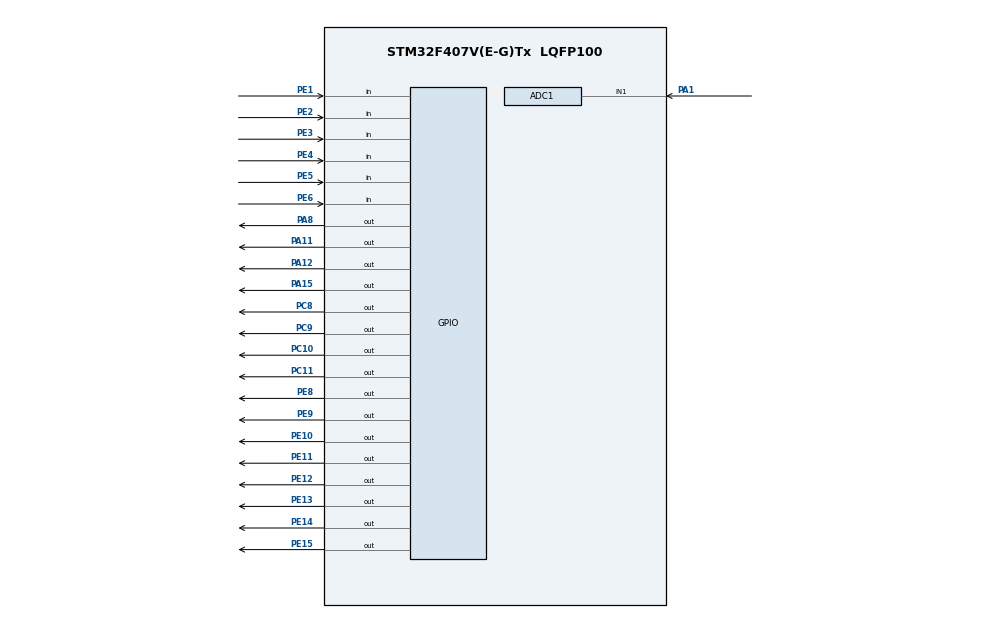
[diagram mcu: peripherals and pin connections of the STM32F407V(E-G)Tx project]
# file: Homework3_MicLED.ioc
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ADC1.Channel-3\#ChannelRegularConversion=ADC_CHANNEL_1
ADC1.Channel-4\#ChannelInjectedConversion=ADC_CHANNEL_1
ADC1.InjNumberOfConversion=1
ADC1.InjectedOffset-4\#ChannelInjectedConversion=0
ADC1.InjectedRank-4\#ChannelInjectedConversion=1
ADC1.NbrOfConversionFlag=1
ADC1.Rank-3\#ChannelRegularConversion=1
ADC1.SamplingTime-3\#ChannelRegularConversion=ADC_SAMPLETIME_480CYCLES
ADC1.SamplingTime-4\#ChannelInjectedConversion=ADC_SAMPLETIME_3CYCLES
ADC1.master=1
FREERTOS.Tasks01=defaultTask,0,128,StartDefaultTask,Default,NULL,Dynamic,NULL,NULL;ledTask,0,128,StartTask02,Default,NULL,Dynamic,NULL,NULL;dispTask,0,128,StartTask03,Default,NULL,Dynamic,NULL,NULL
Mcu.Family=STM32F4
Mcu.Name=STM32F407V(E-G)Tx
Mcu.Package=LQFP100
NVIC.PriorityGroup=NVIC_PRIORITYGROUP_4
NVIC.TIM1_UP_TIM10_IRQn=true\:15\:0\:false\:false\:true\:false\:false\:true\:true
NVIC.TimeBase=TIM1_UP_TIM10_IRQn
NVIC.TimeBaseIP=TIM1
PA1.Signal=ADCx_IN1
PA11.GPIO_Speed=GPIO_SPEED_FREQ_HIGH
PA11.Signal=GPIO_Output
PA12.GPIO_Speed=GPIO_SPEED_FREQ_HIGH
PA12.Signal=GPIO_Output
PA13.Mode=Serial_Wire
PA13.Signal=SYS_JTMS-SWDIO
PA14.Mode=Serial_Wire
PA14.Signal=SYS_JTCK-SWCLK
PA15.GPIO_Speed=GPIO_SPEED_FREQ_HIGH
PA15.Signal=GPIO_Output
PA8.GPIO_Speed=GPIO_SPEED_FREQ_HIGH
PA8.Signal=GPIO_Output
PC10.GPIO_Speed=GPIO_SPEED_FREQ_HIGH
PC10.Signal=GPIO_Output
PC11.GPIO_Speed=GPIO_SPEED_FREQ_HIGH
PC11.Signal=GPIO_Output
PC8.GPIO_Speed=GPIO_SPEED_FREQ_HIGH
PC8.Signal=GPIO_Output
PC9.GPIO_Speed=GPIO_SPEED_FREQ_HIGH
PC9.Signal=GPIO_Output
PE1.GPIO_PuPd=GPIO_PULLUP
PE1.Signal=GPIO_Input
PE10.PinState=GPIO_PIN_SET
PE10.Signal=GPIO_Output
PE11.PinState=GPIO_PIN_SET
PE11.Signal=GPIO_Output
PE12.PinState=GPIO_PIN_SET
PE12.Signal=GPIO_Output
PE13.PinState=GPIO_PIN_SET
PE13.Signal=GPIO_Output
PE14.PinState=GPIO_PIN_SET
PE14.Signal=GPIO_Output
PE15.PinState=GPIO_PIN_SET
PE15.Signal=GPIO_Output
PE2.GPIO_PuPd=GPIO_PULLUP
PE2.Signal=GPIO_Input
PE3.GPIO_PuPd=GPIO_PULLUP
PE3.Signal=GPIO_Input
PE4.GPIO_PuPd=GPIO_PULLUP
PE4.Signal=GPIO_Input
PE5.GPIO_PuPd=GPIO_PULLDOWN
PE5.Signal=GPIO_Input
PE6.GPIO_PuPd=GPIO_PULLDOWN
PE6.Signal=GPIO_Input
PE8.PinState=GPIO_PIN_SET
PE8.Signal=GPIO_Output
PE9.PinState=GPIO_PIN_SET
PE9.Signal=GPIO_Output
PH0-OSC_IN.Mode=HSE-External-Oscillator
PH0-OSC_IN.Signal=RCC_OSC_IN
PH1-OSC_OUT.Mode=HSE-External-Oscillator
PH1-OSC_OUT.Signal=RCC_OSC_OUT
ProjectManager.HeapSize=0x200
ProjectManager.StackSize=0x400
ProjectManager.TargetToolchain=CMake
RCC.48MHZClocksFreq_Value=84000000
RCC.AHBFreq_Value=168000000
RCC.APB1CLKDivider=RCC_HCLK_DIV4
RCC.APB1Freq_Value=42000000
RCC.APB1TimFreq_Value=84000000
RCC.APB2CLKDivider=RCC_HCLK_DIV2
RCC.APB2Freq_Value=84000000
RCC.APB2TimFreq_Value=168000000
RCC.CortexFreq_Value=168000000
RCC.HCLKFreq_Value=168000000
RCC.HSE_VALUE=25000000
RCC.HSI_VALUE=16000000
RCC.LSE_VALUE=32768
RCC.PLLM=8
RCC.PLLN=168
RCC.SYSCLKFreq_VALUE=168000000
RCC.SYSCLKSource=RCC_SYSCLKSOURCE_PLLCLK
RCC.VCOOutputFreq_Value=336000000
SH.ADCx_IN1.0=ADC1_IN1,IN1
VP_FREERTOS_VS_CMSIS_V1.Mode=CMSIS_V1
VP_SYS_VS_tim1.Mode=TIM1
board=custom

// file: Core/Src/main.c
/* USER CODE BEGIN Header */
/**
  ******************************************************************************
  * @file           : main.c
  * @brief          : Main program body
  ******************************************************************************
  * @attention
  *
  * Copyright (c) 2026 STMicroelectronics.
  * All rights reserved.
  *
  * This software is licensed under terms that can be found in the LICENSE file
  * in the root directory of this software component.
  * If no LICENSE file comes with this software, it is provided AS-IS.
  *
  ******************************************************************************
  */
/* USER CODE END Header */
#include "main.h"
#include "cmsis_os.h"
#include "adc.h"
#include "gpio.h"

void SystemClock_Config(void);
void MX_FREERTOS_Init(void);

int main(void)
{

  /* MCU Configuration--------------------------------------------------------*/

  /* Reset of all peripherals, Initializes the Flash interface and the Systick. */
  HAL_Init();

  /* Configure the system clock */
  SystemClock_Config();

  /* Initialize all configured peripherals */
  MX_GPIO_Init();
  MX_ADC1_Init();

  /* Call init function for freertos objects (in cmsis_os2.c) */
  MX_FREERTOS_Init();

  /* Start scheduler */
  osKernelStart();

  /* We should never get here as control is now taken by the scheduler */

  /* Infinite loop */
  while (1)
  {

  }
}

void SystemClock_Config(void)
{
  RCC_OscInitTypeDef RCC_OscInitStruct = {0};
  RCC_ClkInitTypeDef RCC_ClkInitStruct = {0};

  /** Configure the main internal regulator output voltage
  */
  __HAL_RCC_PWR_CLK_ENABLE();
  __HAL_PWR_VOLTAGESCALING_CONFIG(PWR_REGULATOR_VOLTAGE_SCALE1);

  /** Initializes the RCC Oscillators according to the specified parameters
  * in the RCC_OscInitTypeDef structure.
  */
  RCC_OscInitStruct.OscillatorType = RCC_OSCILLATORTYPE_HSE;
  RCC_OscInitStruct.HSEState = RCC_HSE_ON;
  RCC_OscInitStruct.PLL.PLLState = RCC_PLL_ON;
  RCC_OscInitStruct.PLL.PLLSource = RCC_PLLSOURCE_HSE;
  RCC_OscInitStruct.PLL.PLLM = 25;
  RCC_OscInitStruct.PLL.PLLN = 168;
  RCC_OscInitStruct.PLL.PLLP = RCC_PLLP_DIV2;
  RCC_OscInitStruct.PLL.PLLQ = 7;
  if (HAL_RCC_OscConfig(&RCC_OscInitStruct) != HAL_OK)
  {
    Error_Handler();
  }

  /** Initializes the CPU, AHB and APB buses clocks
  */
  RCC_ClkInitStruct.ClockType = RCC_CLOCKTYPE_HCLK|RCC_CLOCKTYPE_SYSCLK
                              |RCC_CLOCKTYPE_PCLK1|RCC_CLOCKTYPE_PCLK2;
  RCC_ClkInitStruct.SYSCLKSource = RCC_SYSCLKSOURCE_PLLCLK;
  RCC_ClkInitStruct.AHBCLKDivider = RCC_SYSCLK_DIV1;
  RCC_ClkInitStruct.APB1CLKDivider = RCC_HCLK_DIV4;
  RCC_ClkInitStruct.APB2CLKDivider = RCC_HCLK_DIV2;

  if (HAL_RCC_ClockConfig(&RCC_ClkInitStruct, FLASH_LATENCY_5) != HAL_OK)
  {
    Error_Handler();
  }
}

void HAL_TIM_PeriodElapsedCallback(TIM_HandleTypeDef *htim)
{
  if (htim->Instance == TIM1)
  {
    HAL_IncTick();
  }
}

void Error_Handler(void)
{
  __disable_irq();
  while (1)
  {
  }
}
